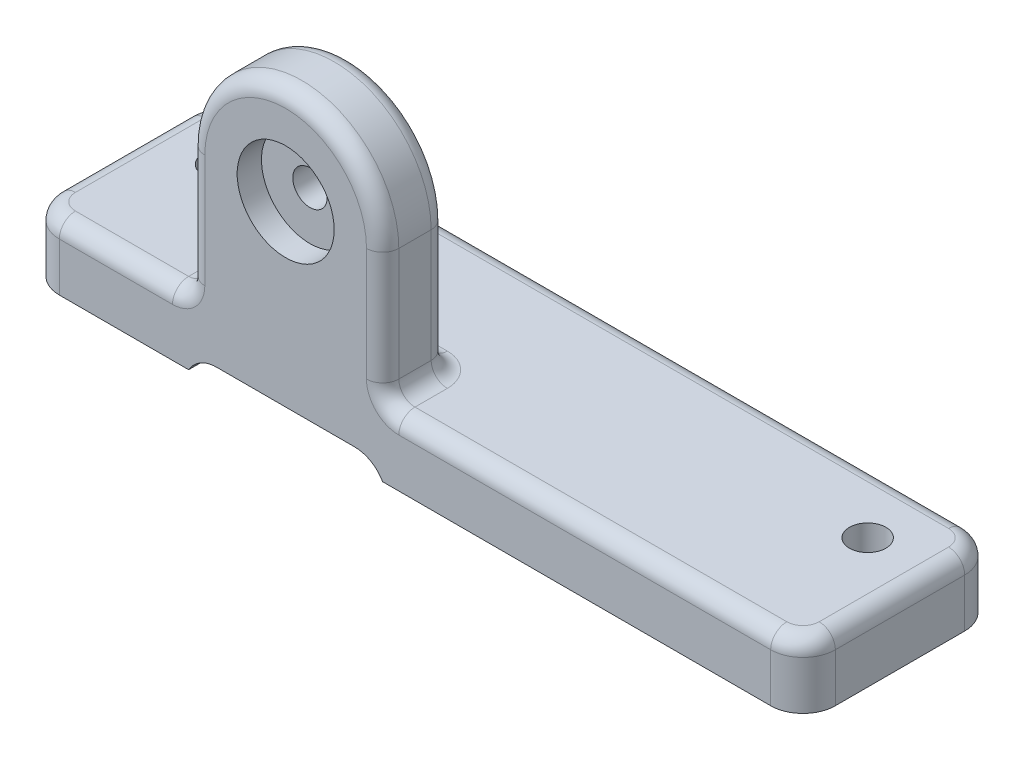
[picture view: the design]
ISO-10303-21;
HEADER;
FILE_DESCRIPTION(('STEP AP214'),'2;1');
FILE_NAME('part.step','',(''),(''),'','','');
FILE_SCHEMA(('AUTOMOTIVE_DESIGN { 1 0 10303 214 1 1 1 1 }'));
ENDSEC;
DATA;
#1=APPLICATION_CONTEXT('core data for automotive mechanical design processes');
#2=APPLICATION_PROTOCOL_DEFINITION('international standard','automotive_design',2000,#1);
#3=PRODUCT_CONTEXT('',#1,'mechanical');
#4=PRODUCT('Part','Part','',(#3));
#5=PRODUCT_RELATED_PRODUCT_CATEGORY('part','',(#4));
#6=PRODUCT_DEFINITION_FORMATION('','',#4);
#7=PRODUCT_DEFINITION_CONTEXT('part definition',#1,'design');
#8=PRODUCT_DEFINITION('design','',#6,#7);
#9=PRODUCT_DEFINITION_SHAPE('','',#8);
#10=(LENGTH_UNIT() NAMED_UNIT(*) SI_UNIT(.MILLI.,.METRE.));
#11=(NAMED_UNIT(*) PLANE_ANGLE_UNIT() SI_UNIT($,.RADIAN.));
#12=(NAMED_UNIT(*) SI_UNIT($,.STERADIAN.) SOLID_ANGLE_UNIT());
#13=UNCERTAINTY_MEASURE_WITH_UNIT(LENGTH_MEASURE(1.E-05),#10,'distance_accuracy_value','');
#14=(GEOMETRIC_REPRESENTATION_CONTEXT(3) GLOBAL_UNCERTAINTY_ASSIGNED_CONTEXT((#13)) GLOBAL_UNIT_ASSIGNED_CONTEXT((#10,
#11,#12)) REPRESENTATION_CONTEXT('',''));
#15=CARTESIAN_POINT('',(0.,0.,0.));
#16=DIRECTION('',(0.,0.,1.));
#17=DIRECTION('',(1.,0.,0.));
#18=AXIS2_PLACEMENT_3D('',#15,#16,#17);
#19=CARTESIAN_POINT('',(0.,0.,-38.1));
#20=DIRECTION('',(0.,-1.,0.));
#21=DIRECTION('',(0.,0.,-1.));
#22=AXIS2_PLACEMENT_3D('',#19,#20,#21);
#23=PLANE('',#22);
#24=CARTESIAN_POINT('',(12.7,0.,-25.4));
#25=DIRECTION('',(0.,1.,0.));
#26=DIRECTION('',(0.,0.,1.));
#27=AXIS2_PLACEMENT_3D('',#24,#25,#26);
#28=CIRCLE('',#27,3.571875);
#29=CARTESIAN_POINT('',(12.7,0.,-21.828125));
#30=VERTEX_POINT('',#29);
#31=EDGE_CURVE('E482',#30,#30,#28,.T.);
#32=ORIENTED_EDGE('',*,*,#31,.T.);
#33=EDGE_LOOP('',(#32));
#34=FACE_BOUND('',#33,.T.);
#35=DIRECTION('',(0.,0.,1.));
#36=VECTOR('',#35,1.);
#37=CARTESIAN_POINT('',(0.,0.,0.));
#38=LINE('',#37,#36);
#39=CARTESIAN_POINT('',(0.,0.,-31.75));
#40=VERTEX_POINT('',#39);
#41=CARTESIAN_POINT('',(0.,0.,-6.35));
#42=VERTEX_POINT('',#41);
#43=EDGE_CURVE('E273',#40,#42,#38,.T.);
#44=ORIENTED_EDGE('',*,*,#43,.F.);
#45=CARTESIAN_POINT('',(6.35,0.,-31.75));
#46=DIRECTION('',(0.,-1.,0.));
#47=DIRECTION('',(0.,0.,-1.));
#48=AXIS2_PLACEMENT_3D('',#45,#46,#47);
#49=CIRCLE('',#48,6.35);
#50=CARTESIAN_POINT('',(6.35,0.,-38.1));
#51=VERTEX_POINT('',#50);
#52=EDGE_CURVE('E247',#40,#51,#49,.T.);
#53=ORIENTED_EDGE('',*,*,#52,.T.);
#54=DIRECTION('',(-1.,0.,0.));
#55=VECTOR('',#54,1.);
#56=CARTESIAN_POINT('',(0.,0.,-38.1));
#57=LINE('',#56,#55);
#58=CARTESIAN_POINT('',(31.75,0.,-38.1));
#59=VERTEX_POINT('',#58);
#60=EDGE_CURVE('E235',#59,#51,#57,.T.);
#61=ORIENTED_EDGE('',*,*,#60,.F.);
#62=DIRECTION('',(0.,0.,1.));
#63=VECTOR('',#62,1.);
#64=CARTESIAN_POINT('',(31.75,0.,-38.1));
#65=LINE('',#64,#63);
#66=CARTESIAN_POINT('',(31.75,0.,0.));
#67=VERTEX_POINT('',#66);
#68=EDGE_CURVE('E246',#59,#67,#65,.T.);
#69=ORIENTED_EDGE('',*,*,#68,.T.);
#70=DIRECTION('',(1.,0.,0.));
#71=VECTOR('',#70,1.);
#72=CARTESIAN_POINT('',(0.,0.,0.));
#73=LINE('',#72,#71);
#74=CARTESIAN_POINT('',(6.35,0.,0.));
#75=VERTEX_POINT('',#74);
#76=EDGE_CURVE('E281',#75,#67,#73,.T.);
#77=ORIENTED_EDGE('',*,*,#76,.F.);
#78=CARTESIAN_POINT('',(6.35,0.,-6.35));
#79=DIRECTION('',(0.,-1.,0.));
#80=DIRECTION('',(0.,0.,-1.));
#81=AXIS2_PLACEMENT_3D('',#78,#79,#80);
#82=CIRCLE('',#81,6.35);
#83=EDGE_CURVE('E314',#75,#42,#82,.T.);
#84=ORIENTED_EDGE('',*,*,#83,.T.);
#85=EDGE_LOOP('',(#44,#53,#61,#69,#77,#84));
#86=FACE_BOUND('',#85,.T.);
#87=ADVANCED_FACE('F43',(#34,#86),#23,.T.);
#88=CARTESIAN_POINT('',(0.,12.7,0.));
#89=DIRECTION('',(1.,0.,0.));
#90=DIRECTION('',(0.,0.,-1.));
#91=AXIS2_PLACEMENT_3D('',#88,#89,#90);
#92=PLANE('',#91);
#93=DIRECTION('',(0.,-1.,0.));
#94=VECTOR('',#93,1.);
#95=CARTESIAN_POINT('',(0.,12.7,-6.35));
#96=LINE('',#95,#94);
#97=CARTESIAN_POINT('',(0.,9.525,-6.35));
#98=VERTEX_POINT('',#97);
#99=EDGE_CURVE('E309',#42,#98,#96,.F.);
#100=ORIENTED_EDGE('',*,*,#99,.T.);
#101=DIRECTION('',(0.,0.,1.));
#102=VECTOR('',#101,1.);
#103=CARTESIAN_POINT('',(0.,9.525,0.));
#104=LINE('',#103,#102);
#105=CARTESIAN_POINT('',(0.,9.525,-31.75));
#106=VERTEX_POINT('',#105);
#107=EDGE_CURVE('E358',#98,#106,#104,.F.);
#108=ORIENTED_EDGE('',*,*,#107,.T.);
#109=DIRECTION('',(0.,-1.,0.));
#110=VECTOR('',#109,1.);
#111=CARTESIAN_POINT('',(0.,12.7,-31.75));
#112=LINE('',#111,#110);
#113=EDGE_CURVE('E312',#106,#40,#112,.T.);
#114=ORIENTED_EDGE('',*,*,#113,.T.);
#115=ORIENTED_EDGE('',*,*,#43,.T.);
#116=EDGE_LOOP('',(#100,#108,#114,#115));
#117=FACE_BOUND('',#116,.T.);
#118=ADVANCED_FACE('F506',(#117),#92,.F.);
#119=CARTESIAN_POINT('',(0.,12.7,0.));
#120=DIRECTION('',(0.,0.,-1.));
#121=DIRECTION('',(-1.,0.,0.));
#122=AXIS2_PLACEMENT_3D('',#119,#120,#121);
#123=PLANE('',#122);
#124=CARTESIAN_POINT('',(50.8,38.1,0.));
#125=DIRECTION('',(0.,0.,1.));
#126=DIRECTION('',(1.,0.,0.));
#127=AXIS2_PLACEMENT_3D('',#124,#125,#126);
#128=CIRCLE('',#127,9.52499999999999);
#129=CARTESIAN_POINT('',(60.325,38.1,0.));
#130=VERTEX_POINT('',#129);
#131=EDGE_CURVE('E268',#130,#130,#128,.T.);
#132=ORIENTED_EDGE('',*,*,#131,.F.);
#133=EDGE_LOOP('',(#132));
#134=FACE_BOUND('',#133,.T.);
#135=CARTESIAN_POINT('',(28.575,15.875,0.));
#136=DIRECTION('',(0.,0.,-1.));
#137=DIRECTION('',(-1.,0.,0.));
#138=AXIS2_PLACEMENT_3D('',#135,#136,#137);
#139=CIRCLE('',#138,6.35);
#140=CARTESIAN_POINT('',(28.575,9.525,0.));
#141=VERTEX_POINT('',#140);
#142=CARTESIAN_POINT('',(34.925,15.875,0.));
#143=VERTEX_POINT('',#142);
#144=EDGE_CURVE('E374',#141,#143,#139,.F.);
#145=ORIENTED_EDGE('',*,*,#144,.F.);
#146=DIRECTION('',(1.,0.,0.));
#147=VECTOR('',#146,1.);
#148=CARTESIAN_POINT('',(0.,9.525,0.));
#149=LINE('',#148,#147);
#150=CARTESIAN_POINT('',(6.35,9.525,0.));
#151=VERTEX_POINT('',#150);
#152=EDGE_CURVE('E377',#141,#151,#149,.F.);
#153=ORIENTED_EDGE('',*,*,#152,.T.);
#154=DIRECTION('',(0.,-1.,0.));
#155=VECTOR('',#154,1.);
#156=CARTESIAN_POINT('',(6.35,12.7,0.));
#157=LINE('',#156,#155);
#158=EDGE_CURVE('E297',#151,#75,#157,.T.);
#159=ORIENTED_EDGE('',*,*,#158,.T.);
#160=ORIENTED_EDGE('',*,*,#76,.T.);
#161=CARTESIAN_POINT('',(37.2492613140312,-3.175,0.));
#162=DIRECTION('',(0.,0.,-1.));
#163=DIRECTION('',(-1.,0.,0.));
#164=AXIS2_PLACEMENT_3D('',#161,#162,#163);
#165=CIRCLE('',#164,6.35);
#166=CARTESIAN_POINT('',(37.2492613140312,3.175,0.));
#167=VERTEX_POINT('',#166);
#168=EDGE_CURVE('E239',#67,#167,#165,.T.);
#169=ORIENTED_EDGE('',*,*,#168,.T.);
#170=DIRECTION('',(-1.,0.,0.));
#171=VECTOR('',#170,1.);
#172=CARTESIAN_POINT('',(31.75,3.175,0.));
#173=LINE('',#172,#171);
#174=CARTESIAN_POINT('',(64.3507386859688,3.175,0.));
#175=VERTEX_POINT('',#174);
#176=EDGE_CURVE('E256',#175,#167,#173,.T.);
#177=ORIENTED_EDGE('',*,*,#176,.F.);
#178=CARTESIAN_POINT('',(64.3507386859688,-3.175,0.));
#179=DIRECTION('',(0.,0.,-1.));
#180=DIRECTION('',(-1.,0.,0.));
#181=AXIS2_PLACEMENT_3D('',#178,#179,#180);
#182=CIRCLE('',#181,6.35);
#183=CARTESIAN_POINT('',(69.85,0.,0.));
#184=VERTEX_POINT('',#183);
#185=EDGE_CURVE('E319',#175,#184,#182,.T.);
#186=ORIENTED_EDGE('',*,*,#185,.T.);
#187=CARTESIAN_POINT('',(146.05,0.,0.));
#188=VERTEX_POINT('',#187);
#189=EDGE_CURVE('E278',#184,#188,#73,.T.);
#190=ORIENTED_EDGE('',*,*,#189,.T.);
#191=DIRECTION('',(0.,-1.,0.));
#192=VECTOR('',#191,1.);
#193=CARTESIAN_POINT('',(146.05,12.7,0.));
#194=LINE('',#193,#192);
#195=CARTESIAN_POINT('',(146.05,9.525,0.));
#196=VERTEX_POINT('',#195);
#197=EDGE_CURVE('E305',#188,#196,#194,.F.);
#198=ORIENTED_EDGE('',*,*,#197,.T.);
#199=DIRECTION('',(1.,0.,0.));
#200=VECTOR('',#199,1.);
#201=CARTESIAN_POINT('',(0.,9.525,0.));
#202=LINE('',#201,#200);
#203=CARTESIAN_POINT('',(73.025,9.525,0.));
#204=VERTEX_POINT('',#203);
#205=EDGE_CURVE('E373',#196,#204,#202,.F.);
#206=ORIENTED_EDGE('',*,*,#205,.T.);
#207=CARTESIAN_POINT('',(73.025,15.875,0.));
#208=DIRECTION('',(0.,0.,-1.));
#209=DIRECTION('',(-1.,0.,0.));
#210=AXIS2_PLACEMENT_3D('',#207,#208,#209);
#211=CIRCLE('',#210,6.35);
#212=CARTESIAN_POINT('',(66.675,15.875,0.));
#213=VERTEX_POINT('',#212);
#214=EDGE_CURVE('E369',#213,#204,#211,.F.);
#215=ORIENTED_EDGE('',*,*,#214,.F.);
#216=DIRECTION('',(0.,1.,0.));
#217=VECTOR('',#216,1.);
#218=CARTESIAN_POINT('',(66.675,38.1,0.));
#219=LINE('',#218,#217);
#220=CARTESIAN_POINT('',(66.675,38.1,0.));
#221=VERTEX_POINT('',#220);
#222=EDGE_CURVE('E364',#213,#221,#219,.T.);
#223=ORIENTED_EDGE('',*,*,#222,.T.);
#224=CARTESIAN_POINT('',(50.8,38.1,0.));
#225=DIRECTION('',(0.,0.,-1.));
#226=DIRECTION('',(-1.,0.,0.));
#227=AXIS2_PLACEMENT_3D('',#224,#225,#226);
#228=CIRCLE('',#227,15.875);
#229=CARTESIAN_POINT('',(34.925,38.1,0.));
#230=VERTEX_POINT('',#229);
#231=EDGE_CURVE('E366',#221,#230,#228,.F.);
#232=ORIENTED_EDGE('',*,*,#231,.T.);
#233=DIRECTION('',(0.,-1.,0.));
#234=VECTOR('',#233,1.);
#235=CARTESIAN_POINT('',(34.925,12.7,0.));
#236=LINE('',#235,#234);
#237=EDGE_CURVE('E368',#230,#143,#236,.T.);
#238=ORIENTED_EDGE('',*,*,#237,.T.);
#239=EDGE_LOOP('',(#145,#153,#159,#160,#169,#177,#186,#190,#198,#206,#215,#223,#232,#238));
#240=FACE_BOUND('',#239,.T.);
#241=ADVANCED_FACE('F498',(#134,#240),#123,.F.);
#242=CARTESIAN_POINT('',(152.4,12.7,0.));
#243=DIRECTION('',(-1.,0.,0.));
#244=DIRECTION('',(0.,0.,1.));
#245=AXIS2_PLACEMENT_3D('',#242,#243,#244);
#246=PLANE('',#245);
#247=DIRECTION('',(0.,-1.,0.));
#248=VECTOR('',#247,1.);
#249=CARTESIAN_POINT('',(152.4,12.7,-31.75));
#250=LINE('',#249,#248);
#251=CARTESIAN_POINT('',(152.4,0.,-31.75));
#252=VERTEX_POINT('',#251);
#253=CARTESIAN_POINT('',(152.4,9.525,-31.75));
#254=VERTEX_POINT('',#253);
#255=EDGE_CURVE('E300',#252,#254,#250,.F.);
#256=ORIENTED_EDGE('',*,*,#255,.T.);
#257=DIRECTION('',(0.,0.,-1.));
#258=VECTOR('',#257,1.);
#259=CARTESIAN_POINT('',(152.4,9.525,0.));
#260=LINE('',#259,#258);
#261=CARTESIAN_POINT('',(152.4,9.525,-6.35));
#262=VERTEX_POINT('',#261);
#263=EDGE_CURVE('E379',#254,#262,#260,.F.);
#264=ORIENTED_EDGE('',*,*,#263,.T.);
#265=DIRECTION('',(0.,-1.,0.));
#266=VECTOR('',#265,1.);
#267=CARTESIAN_POINT('',(152.4,12.7,-6.35));
#268=LINE('',#267,#266);
#269=CARTESIAN_POINT('',(152.4,0.,-6.35));
#270=VERTEX_POINT('',#269);
#271=EDGE_CURVE('E294',#262,#270,#268,.T.);
#272=ORIENTED_EDGE('',*,*,#271,.T.);
#273=DIRECTION('',(0.,0.,-1.));
#274=VECTOR('',#273,1.);
#275=CARTESIAN_POINT('',(152.4,0.,0.));
#276=LINE('',#275,#274);
#277=EDGE_CURVE('E249',#270,#252,#276,.T.);
#278=ORIENTED_EDGE('',*,*,#277,.T.);
#279=EDGE_LOOP('',(#256,#264,#272,#278));
#280=FACE_BOUND('',#279,.T.);
#281=ADVANCED_FACE('F547',(#280),#246,.F.);
#282=CARTESIAN_POINT('',(0.,12.7,-38.1));
#283=DIRECTION('',(0.,0.,1.));
#284=DIRECTION('',(1.,0.,0.));
#285=AXIS2_PLACEMENT_3D('',#282,#283,#284);
#286=PLANE('',#285);
#287=DIRECTION('',(0.,-1.,0.));
#288=VECTOR('',#287,1.);
#289=CARTESIAN_POINT('',(6.35,12.7,-38.1));
#290=LINE('',#289,#288);
#291=CARTESIAN_POINT('',(6.35,9.525,-38.1));
#292=VERTEX_POINT('',#291);
#293=EDGE_CURVE('E284',#51,#292,#290,.F.);
#294=ORIENTED_EDGE('',*,*,#293,.T.);
#295=DIRECTION('',(-1.,0.,0.));
#296=VECTOR('',#295,1.);
#297=CARTESIAN_POINT('',(0.,9.525,-38.1));
#298=LINE('',#297,#296);
#299=CARTESIAN_POINT('',(146.05,9.525,-38.1));
#300=VERTEX_POINT('',#299);
#301=EDGE_CURVE('E356',#292,#300,#298,.F.);
#302=ORIENTED_EDGE('',*,*,#301,.T.);
#303=DIRECTION('',(0.,-1.,0.));
#304=VECTOR('',#303,1.);
#305=CARTESIAN_POINT('',(146.05,12.7,-38.1));
#306=LINE('',#305,#304);
#307=CARTESIAN_POINT('',(146.05,0.,-38.1));
#308=VERTEX_POINT('',#307);
#309=EDGE_CURVE('E288',#300,#308,#306,.T.);
#310=ORIENTED_EDGE('',*,*,#309,.T.);
#311=CARTESIAN_POINT('',(69.85,0.,-38.1));
#312=VERTEX_POINT('',#311);
#313=EDGE_CURVE('E248',#308,#312,#57,.T.);
#314=ORIENTED_EDGE('',*,*,#313,.T.);
#315=CARTESIAN_POINT('',(64.3507386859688,-3.175,-38.1));
#316=DIRECTION('',(0.,0.,1.));
#317=DIRECTION('',(1.,0.,0.));
#318=AXIS2_PLACEMENT_3D('',#315,#316,#317);
#319=CIRCLE('',#318,6.35);
#320=CARTESIAN_POINT('',(64.3507386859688,3.175,-38.1));
#321=VERTEX_POINT('',#320);
#322=EDGE_CURVE('E318',#312,#321,#319,.T.);
#323=ORIENTED_EDGE('',*,*,#322,.T.);
#324=DIRECTION('',(-1.,0.,0.));
#325=VECTOR('',#324,1.);
#326=CARTESIAN_POINT('',(31.75,3.175,-38.1));
#327=LINE('',#326,#325);
#328=CARTESIAN_POINT('',(37.2492613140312,3.175,-38.1));
#329=VERTEX_POINT('',#328);
#330=EDGE_CURVE('E232',#321,#329,#327,.T.);
#331=ORIENTED_EDGE('',*,*,#330,.T.);
#332=CARTESIAN_POINT('',(37.2492613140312,-3.175,-38.1));
#333=DIRECTION('',(0.,0.,1.));
#334=DIRECTION('',(1.,0.,0.));
#335=AXIS2_PLACEMENT_3D('',#332,#333,#334);
#336=CIRCLE('',#335,6.35);
#337=EDGE_CURVE('E226',#329,#59,#336,.T.);
#338=ORIENTED_EDGE('',*,*,#337,.T.);
#339=ORIENTED_EDGE('',*,*,#60,.T.);
#340=EDGE_LOOP('',(#294,#302,#310,#314,#323,#331,#338,#339));
#341=FACE_BOUND('',#340,.T.);
#342=ADVANCED_FACE('F233',(#341),#286,.F.);
#343=CARTESIAN_POINT('',(0.,12.7,-38.1));
#344=DIRECTION('',(0.,-1.,0.));
#345=DIRECTION('',(0.,0.,-1.));
#346=AXIS2_PLACEMENT_3D('',#343,#344,#345);
#347=PLANE('',#346);
#348=DIRECTION('',(-1.,0.,0.));
#349=VECTOR('',#348,1.);
#350=CARTESIAN_POINT('',(0.,12.7,-34.925));
#351=LINE('',#350,#349);
#352=CARTESIAN_POINT('',(146.05,12.7,-34.925));
#353=VERTEX_POINT('',#352);
#354=CARTESIAN_POINT('',(6.35,12.7,-34.925));
#355=VERTEX_POINT('',#354);
#356=EDGE_CURVE('E346',#353,#355,#351,.T.);
#357=ORIENTED_EDGE('',*,*,#356,.T.);
#358=CARTESIAN_POINT('',(6.35,12.7,-31.75));
#359=DIRECTION('',(0.,-1.,0.));
#360=DIRECTION('',(0.,0.,-1.));
#361=AXIS2_PLACEMENT_3D('',#358,#359,#360);
#362=CIRCLE('',#361,3.175);
#363=CARTESIAN_POINT('',(3.175,12.7,-31.75));
#364=VERTEX_POINT('',#363);
#365=EDGE_CURVE('E349',#355,#364,#362,.F.);
#366=ORIENTED_EDGE('',*,*,#365,.T.);
#367=DIRECTION('',(0.,0.,1.));
#368=VECTOR('',#367,1.);
#369=CARTESIAN_POINT('',(3.175,12.7,-38.1));
#370=LINE('',#369,#368);
#371=CARTESIAN_POINT('',(3.175,12.7,-6.35));
#372=VERTEX_POINT('',#371);
#373=EDGE_CURVE('E347',#364,#372,#370,.T.);
#374=ORIENTED_EDGE('',*,*,#373,.T.);
#375=CARTESIAN_POINT('',(6.35,12.7,-6.35));
#376=DIRECTION('',(0.,-1.,0.));
#377=DIRECTION('',(0.,0.,-1.));
#378=AXIS2_PLACEMENT_3D('',#375,#376,#377);
#379=CIRCLE('',#378,3.175);
#380=CARTESIAN_POINT('',(6.35,12.7,-3.175));
#381=VERTEX_POINT('',#380);
#382=EDGE_CURVE('E341',#372,#381,#379,.F.);
#383=ORIENTED_EDGE('',*,*,#382,.T.);
#384=DIRECTION('',(1.,0.,0.));
#385=VECTOR('',#384,1.);
#386=CARTESIAN_POINT('',(0.,12.7,-3.175));
#387=LINE('',#386,#385);
#388=CARTESIAN_POINT('',(28.575,12.7,-3.175));
#389=VERTEX_POINT('',#388);
#390=EDGE_CURVE('E338',#381,#389,#387,.T.);
#391=ORIENTED_EDGE('',*,*,#390,.T.);
#392=DIRECTION('',(0.,0.,-1.));
#393=VECTOR('',#392,1.);
#394=CARTESIAN_POINT('',(28.575,12.7,-38.1));
#395=LINE('',#394,#393);
#396=CARTESIAN_POINT('',(28.575,12.7,-9.525));
#397=VERTEX_POINT('',#396);
#398=EDGE_CURVE('E337',#389,#397,#395,.T.);
#399=ORIENTED_EDGE('',*,*,#398,.T.);
#400=CARTESIAN_POINT('',(34.925,12.7,-9.525));
#401=DIRECTION('',(0.,-1.,0.));
#402=DIRECTION('',(0.,0.,-1.));
#403=AXIS2_PLACEMENT_3D('',#400,#401,#402);
#404=CIRCLE('',#403,6.35);
#405=CARTESIAN_POINT('',(34.925,12.7,-15.875));
#406=VERTEX_POINT('',#405);
#407=EDGE_CURVE('E333',#406,#397,#404,.F.);
#408=ORIENTED_EDGE('',*,*,#407,.F.);
#409=DIRECTION('',(1.,0.,0.));
#410=VECTOR('',#409,1.);
#411=CARTESIAN_POINT('',(0.,12.7,-15.875));
#412=LINE('',#411,#410);
#413=CARTESIAN_POINT('',(66.675,12.7,-15.875));
#414=VERTEX_POINT('',#413);
#415=EDGE_CURVE('E328',#406,#414,#412,.T.);
#416=ORIENTED_EDGE('',*,*,#415,.T.);
#417=CARTESIAN_POINT('',(66.675,12.7,-9.525));
#418=DIRECTION('',(0.,-1.,0.));
#419=DIRECTION('',(0.,0.,-1.));
#420=AXIS2_PLACEMENT_3D('',#417,#418,#419);
#421=CIRCLE('',#420,6.35);
#422=CARTESIAN_POINT('',(73.025,12.7,-9.525));
#423=VERTEX_POINT('',#422);
#424=EDGE_CURVE('E326',#423,#414,#421,.F.);
#425=ORIENTED_EDGE('',*,*,#424,.F.);
#426=DIRECTION('',(0.,0.,1.));
#427=VECTOR('',#426,1.);
#428=CARTESIAN_POINT('',(73.025,12.7,-38.1));
#429=LINE('',#428,#427);
#430=CARTESIAN_POINT('',(73.025,12.7,-3.175));
#431=VERTEX_POINT('',#430);
#432=EDGE_CURVE('E237',#423,#431,#429,.T.);
#433=ORIENTED_EDGE('',*,*,#432,.T.);
#434=DIRECTION('',(1.,0.,0.));
#435=VECTOR('',#434,1.);
#436=CARTESIAN_POINT('',(0.,12.7,-3.175));
#437=LINE('',#436,#435);
#438=CARTESIAN_POINT('',(146.05,12.7,-3.175));
#439=VERTEX_POINT('',#438);
#440=EDGE_CURVE('E321',#431,#439,#437,.T.);
#441=ORIENTED_EDGE('',*,*,#440,.T.);
#442=CARTESIAN_POINT('',(146.05,12.7,-6.35));
#443=DIRECTION('',(0.,-1.,0.));
#444=DIRECTION('',(0.,0.,-1.));
#445=AXIS2_PLACEMENT_3D('',#442,#443,#444);
#446=CIRCLE('',#445,3.175);
#447=CARTESIAN_POINT('',(149.225,12.7,-6.35));
#448=VERTEX_POINT('',#447);
#449=EDGE_CURVE('E332',#439,#448,#446,.F.);
#450=ORIENTED_EDGE('',*,*,#449,.T.);
#451=DIRECTION('',(0.,0.,-1.));
#452=VECTOR('',#451,1.);
#453=CARTESIAN_POINT('',(149.225,12.7,-38.1));
#454=LINE('',#453,#452);
#455=CARTESIAN_POINT('',(149.225,12.7,-31.75));
#456=VERTEX_POINT('',#455);
#457=EDGE_CURVE('E336',#448,#456,#454,.T.);
#458=ORIENTED_EDGE('',*,*,#457,.T.);
#459=CARTESIAN_POINT('',(146.05,12.7,-31.75));
#460=DIRECTION('',(0.,-1.,0.));
#461=DIRECTION('',(0.,0.,-1.));
#462=AXIS2_PLACEMENT_3D('',#459,#460,#461);
#463=CIRCLE('',#462,3.175);
#464=EDGE_CURVE('E345',#456,#353,#463,.F.);
#465=ORIENTED_EDGE('',*,*,#464,.T.);
#466=EDGE_LOOP('',(#357,#366,#374,#383,#391,#399,#408,#416,#425,#433,#441,#450,#458,#465));
#467=FACE_BOUND('',#466,.T.);
#468=CARTESIAN_POINT('',(139.7,12.7,-25.4));
#469=DIRECTION('',(0.,1.,0.));
#470=DIRECTION('',(0.,0.,1.));
#471=AXIS2_PLACEMENT_3D('',#468,#469,#470);
#472=CIRCLE('',#471,3.57187499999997);
#473=CARTESIAN_POINT('',(139.7,12.7,-21.828125));
#474=VERTEX_POINT('',#473);
#475=EDGE_CURVE('E479',#474,#474,#472,.T.);
#476=ORIENTED_EDGE('',*,*,#475,.F.);
#477=EDGE_LOOP('',(#476));
#478=FACE_BOUND('',#477,.T.);
#479=CARTESIAN_POINT('',(12.7,12.7,-25.4));
#480=DIRECTION('',(0.,1.,0.));
#481=DIRECTION('',(0.,0.,1.));
#482=AXIS2_PLACEMENT_3D('',#479,#480,#481);
#483=CIRCLE('',#482,3.57187499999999);
#484=CARTESIAN_POINT('',(12.7,12.7,-21.828125));
#485=VERTEX_POINT('',#484);
#486=EDGE_CURVE('E489',#485,#485,#483,.T.);
#487=ORIENTED_EDGE('',*,*,#486,.F.);
#488=EDGE_LOOP('',(#487));
#489=FACE_BOUND('',#488,.T.);
#490=ADVANCED_FACE('F594',(#467,#478,#489),#347,.F.);
#491=CARTESIAN_POINT('',(139.7,0.,-25.4));
#492=DIRECTION('',(0.,1.,0.));
#493=DIRECTION('',(0.,0.,1.));
#494=AXIS2_PLACEMENT_3D('',#491,#492,#493);
#495=CIRCLE('',#494,3.571875);
#496=CARTESIAN_POINT('',(139.7,0.,-21.828125));
#497=VERTEX_POINT('',#496);
#498=EDGE_CURVE('E471',#497,#497,#495,.T.);
#499=ORIENTED_EDGE('',*,*,#498,.T.);
#500=EDGE_LOOP('',(#499));
#501=FACE_BOUND('',#500,.T.);
#502=ORIENTED_EDGE('',*,*,#313,.F.);
#503=CARTESIAN_POINT('',(146.05,0.,-31.75));
#504=DIRECTION('',(0.,-1.,0.));
#505=DIRECTION('',(0.,0.,-1.));
#506=AXIS2_PLACEMENT_3D('',#503,#504,#505);
#507=CIRCLE('',#506,6.35);
#508=EDGE_CURVE('E291',#308,#252,#507,.T.);
#509=ORIENTED_EDGE('',*,*,#508,.T.);
#510=ORIENTED_EDGE('',*,*,#277,.F.);
#511=CARTESIAN_POINT('',(146.05,0.,-6.35));
#512=DIRECTION('',(0.,-1.,0.));
#513=DIRECTION('',(0.,0.,-1.));
#514=AXIS2_PLACEMENT_3D('',#511,#512,#513);
#515=CIRCLE('',#514,6.35);
#516=EDGE_CURVE('E293',#270,#188,#515,.T.);
#517=ORIENTED_EDGE('',*,*,#516,.T.);
#518=ORIENTED_EDGE('',*,*,#189,.F.);
#519=DIRECTION('',(0.,0.,1.));
#520=VECTOR('',#519,1.);
#521=CARTESIAN_POINT('',(69.85,0.,-38.1));
#522=LINE('',#521,#520);
#523=EDGE_CURVE('E251',#312,#184,#522,.T.);
#524=ORIENTED_EDGE('',*,*,#523,.F.);
#525=EDGE_LOOP('',(#502,#509,#510,#517,#518,#524));
#526=FACE_BOUND('',#525,.T.);
#527=ADVANCED_FACE('F626',(#501,#526),#23,.T.);
#528=CARTESIAN_POINT('',(31.75,0.,-12.7));
#529=DIRECTION('',(-1.,0.,0.));
#530=DIRECTION('',(0.,0.,1.));
#531=AXIS2_PLACEMENT_3D('',#528,#529,#530);
#532=PLANE('',#531);
#533=DIRECTION('',(0.,0.,1.));
#534=VECTOR('',#533,1.);
#535=CARTESIAN_POINT('',(31.75,38.1,-12.7));
#536=LINE('',#535,#534);
#537=CARTESIAN_POINT('',(31.75,38.1,-9.525));
#538=VERTEX_POINT('',#537);
#539=CARTESIAN_POINT('',(31.75,38.1,-3.175));
#540=VERTEX_POINT('',#539);
#541=EDGE_CURVE('E275',#538,#540,#536,.T.);
#542=ORIENTED_EDGE('',*,*,#541,.F.);
#543=DIRECTION('',(0.,-1.,0.));
#544=VECTOR('',#543,1.);
#545=CARTESIAN_POINT('',(31.75,0.,-9.525));
#546=LINE('',#545,#544);
#547=CARTESIAN_POINT('',(31.75,15.875,-9.525));
#548=VERTEX_POINT('',#547);
#549=EDGE_CURVE('E390',#538,#548,#546,.T.);
#550=ORIENTED_EDGE('',*,*,#549,.T.);
#551=DIRECTION('',(0.,0.,-1.));
#552=VECTOR('',#551,1.);
#553=CARTESIAN_POINT('',(31.75,15.875,-12.7));
#554=LINE('',#553,#552);
#555=CARTESIAN_POINT('',(31.75,15.875,-3.175));
#556=VERTEX_POINT('',#555);
#557=EDGE_CURVE('E381',#548,#556,#554,.F.);
#558=ORIENTED_EDGE('',*,*,#557,.T.);
#559=DIRECTION('',(0.,-1.,0.));
#560=VECTOR('',#559,1.);
#561=CARTESIAN_POINT('',(31.75,38.1,-3.175));
#562=LINE('',#561,#560);
#563=EDGE_CURVE('E385',#556,#540,#562,.F.);
#564=ORIENTED_EDGE('',*,*,#563,.T.);
#565=EDGE_LOOP('',(#542,#550,#558,#564));
#566=FACE_BOUND('',#565,.T.);
#567=ADVANCED_FACE('F634',(#566),#532,.T.);
#568=CARTESIAN_POINT('',(69.85,0.,-12.7));
#569=DIRECTION('',(1.,0.,0.));
#570=DIRECTION('',(0.,0.,-1.));
#571=AXIS2_PLACEMENT_3D('',#568,#569,#570);
#572=PLANE('',#571);
#573=DIRECTION('',(0.,0.,1.));
#574=VECTOR('',#573,1.);
#575=CARTESIAN_POINT('',(69.85,15.875,-12.7));
#576=LINE('',#575,#574);
#577=CARTESIAN_POINT('',(69.85,15.875,-3.175));
#578=VERTEX_POINT('',#577);
#579=CARTESIAN_POINT('',(69.85,15.875,-9.525));
#580=VERTEX_POINT('',#579);
#581=EDGE_CURVE('E55',#578,#580,#576,.F.);
#582=ORIENTED_EDGE('',*,*,#581,.T.);
#583=DIRECTION('',(0.,1.,0.));
#584=VECTOR('',#583,1.);
#585=CARTESIAN_POINT('',(69.85,0.,-9.525));
#586=LINE('',#585,#584);
#587=CARTESIAN_POINT('',(69.85,38.1,-9.525));
#588=VERTEX_POINT('',#587);
#589=EDGE_CURVE('E11',#580,#588,#586,.T.);
#590=ORIENTED_EDGE('',*,*,#589,.T.);
#591=DIRECTION('',(0.,0.,1.));
#592=VECTOR('',#591,1.);
#593=CARTESIAN_POINT('',(69.85,38.1,-12.7));
#594=LINE('',#593,#592);
#595=CARTESIAN_POINT('',(69.85,38.1,-3.175));
#596=VERTEX_POINT('',#595);
#597=EDGE_CURVE('E277',#588,#596,#594,.T.);
#598=ORIENTED_EDGE('',*,*,#597,.T.);
#599=DIRECTION('',(0.,1.,0.));
#600=VECTOR('',#599,1.);
#601=CARTESIAN_POINT('',(69.85,12.7,-3.175));
#602=LINE('',#601,#600);
#603=EDGE_CURVE('E64',#596,#578,#602,.F.);
#604=ORIENTED_EDGE('',*,*,#603,.T.);
#605=EDGE_LOOP('',(#582,#590,#598,#604));
#606=FACE_BOUND('',#605,.T.);
#607=ADVANCED_FACE('F639',(#606),#572,.T.);
#608=CARTESIAN_POINT('',(50.8,38.1,-12.7));
#609=DIRECTION('',(0.,0.,-1.));
#610=DIRECTION('',(-1.,0.,0.));
#611=AXIS2_PLACEMENT_3D('',#608,#609,#610);
#612=PLANE('',#611);
#613=DIRECTION('',(0.,1.,0.));
#614=VECTOR('',#613,1.);
#615=CARTESIAN_POINT('',(66.675,38.1,-12.7));
#616=LINE('',#615,#614);
#617=CARTESIAN_POINT('',(66.675,38.1,-12.7));
#618=VERTEX_POINT('',#617);
#619=CARTESIAN_POINT('',(66.675,15.875,-12.7));
#620=VERTEX_POINT('',#619);
#621=EDGE_CURVE('E391',#618,#620,#616,.F.);
#622=ORIENTED_EDGE('',*,*,#621,.T.);
#623=DIRECTION('',(1.,0.,0.));
#624=VECTOR('',#623,1.);
#625=CARTESIAN_POINT('',(50.8,15.875,-12.7));
#626=LINE('',#625,#624);
#627=CARTESIAN_POINT('',(34.925,15.875,-12.7));
#628=VERTEX_POINT('',#627);
#629=EDGE_CURVE('E400',#620,#628,#626,.F.);
#630=ORIENTED_EDGE('',*,*,#629,.T.);
#631=DIRECTION('',(0.,-1.,0.));
#632=VECTOR('',#631,1.);
#633=CARTESIAN_POINT('',(34.925,38.1,-12.7));
#634=LINE('',#633,#632);
#635=CARTESIAN_POINT('',(34.925,38.1,-12.7));
#636=VERTEX_POINT('',#635);
#637=EDGE_CURVE('E394',#628,#636,#634,.F.);
#638=ORIENTED_EDGE('',*,*,#637,.T.);
#639=CARTESIAN_POINT('',(50.8,38.1,-12.7));
#640=DIRECTION('',(0.,0.,-1.));
#641=DIRECTION('',(-1.,0.,0.));
#642=AXIS2_PLACEMENT_3D('',#639,#640,#641);
#643=CIRCLE('',#642,15.875);
#644=EDGE_CURVE('E392',#636,#618,#643,.T.);
#645=ORIENTED_EDGE('',*,*,#644,.T.);
#646=EDGE_LOOP('',(#622,#630,#638,#645));
#647=FACE_BOUND('',#646,.T.);
#648=CARTESIAN_POINT('',(50.8,38.1,-12.7));
#649=DIRECTION('',(0.,0.,-1.));
#650=DIRECTION('',(-1.,0.,0.));
#651=AXIS2_PLACEMENT_3D('',#648,#649,#650);
#652=CIRCLE('',#651,3.37819999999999);
#653=CARTESIAN_POINT('',(47.4218,38.1,-12.7));
#654=VERTEX_POINT('',#653);
#655=EDGE_CURVE('E272',#654,#654,#652,.T.);
#656=ORIENTED_EDGE('',*,*,#655,.F.);
#657=EDGE_LOOP('',(#656));
#658=FACE_BOUND('',#657,.T.);
#659=ADVANCED_FACE('F702',(#647,#658),#612,.T.);
#660=CARTESIAN_POINT('',(50.8,38.1,-12.7));
#661=DIRECTION('',(0.,0.,1.));
#662=DIRECTION('',(1.,0.,0.));
#663=AXIS2_PLACEMENT_3D('',#660,#661,#662);
#664=CYLINDRICAL_SURFACE('',#663,19.05);
#665=ORIENTED_EDGE('',*,*,#597,.F.);
#666=CARTESIAN_POINT('',(50.8,38.1,-9.525));
#667=DIRECTION('',(0.,0.,-1.));
#668=DIRECTION('',(-1.,0.,0.));
#669=AXIS2_PLACEMENT_3D('',#666,#667,#668);
#670=CIRCLE('',#669,19.05);
#671=EDGE_CURVE('E405',#588,#538,#670,.F.);
#672=ORIENTED_EDGE('',*,*,#671,.T.);
#673=ORIENTED_EDGE('',*,*,#541,.T.);
#674=CARTESIAN_POINT('',(50.8,38.1,-3.175));
#675=DIRECTION('',(0.,0.,-1.));
#676=DIRECTION('',(-1.,0.,0.));
#677=AXIS2_PLACEMENT_3D('',#674,#675,#676);
#678=CIRCLE('',#677,19.05);
#679=EDGE_CURVE('E396',#540,#596,#678,.T.);
#680=ORIENTED_EDGE('',*,*,#679,.T.);
#681=EDGE_LOOP('',(#665,#672,#673,#680));
#682=FACE_BOUND('',#681,.T.);
#683=ADVANCED_FACE('F709',(#682),#664,.T.);
#684=CARTESIAN_POINT('',(50.8,38.1,0.));
#685=DIRECTION('',(0.,0.,1.));
#686=DIRECTION('',(1.,0.,0.));
#687=AXIS2_PLACEMENT_3D('',#684,#685,#686);
#688=CYLINDRICAL_SURFACE('',#687,9.52499999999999);
#689=CARTESIAN_POINT('',(50.8,38.1,-4.7752));
#690=DIRECTION('',(0.,0.,1.));
#691=DIRECTION('',(1.,0.,0.));
#692=AXIS2_PLACEMENT_3D('',#689,#690,#691);
#693=CIRCLE('',#692,9.52499999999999);
#694=CARTESIAN_POINT('',(60.325,38.1,-4.7752));
#695=VERTEX_POINT('',#694);
#696=EDGE_CURVE('E264',#695,#695,#693,.T.);
#697=ORIENTED_EDGE('',*,*,#696,.F.);
#698=EDGE_LOOP('',(#697));
#699=FACE_BOUND('',#698,.T.);
#700=ORIENTED_EDGE('',*,*,#131,.T.);
#701=EDGE_LOOP('',(#700));
#702=FACE_BOUND('',#701,.T.);
#703=ADVANCED_FACE('F712',(#699,#702),#688,.F.);
#704=CARTESIAN_POINT('',(54.1782,38.1,-4.7752));
#705=DIRECTION('',(0.,0.,-1.));
#706=DIRECTION('',(-1.,0.,0.));
#707=AXIS2_PLACEMENT_3D('',#704,#705,#706);
#708=PLANE('',#707);
#709=CARTESIAN_POINT('',(50.8,38.1,-4.7752));
#710=DIRECTION('',(0.,0.,1.));
#711=DIRECTION('',(1.,0.,0.));
#712=AXIS2_PLACEMENT_3D('',#709,#710,#711);
#713=CIRCLE('',#712,3.3782);
#714=CARTESIAN_POINT('',(54.1782,38.1,-4.7752));
#715=VERTEX_POINT('',#714);
#716=EDGE_CURVE('E260',#715,#715,#713,.T.);
#717=ORIENTED_EDGE('',*,*,#716,.F.);
#718=EDGE_LOOP('',(#717));
#719=FACE_BOUND('',#718,.T.);
#720=ORIENTED_EDGE('',*,*,#696,.T.);
#721=EDGE_LOOP('',(#720));
#722=FACE_BOUND('',#721,.T.);
#723=ADVANCED_FACE('F717',(#719,#722),#708,.F.);
#724=CARTESIAN_POINT('',(50.8,38.1,0.));
#725=DIRECTION('',(0.,0.,1.));
#726=DIRECTION('',(1.,0.,0.));
#727=AXIS2_PLACEMENT_3D('',#724,#725,#726);
#728=CYLINDRICAL_SURFACE('',#727,3.37819999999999);
#729=ORIENTED_EDGE('',*,*,#655,.T.);
#730=EDGE_LOOP('',(#729));
#731=FACE_BOUND('',#730,.T.);
#732=ORIENTED_EDGE('',*,*,#716,.T.);
#733=EDGE_LOOP('',(#732));
#734=FACE_BOUND('',#733,.T.);
#735=ADVANCED_FACE('F742',(#731,#734),#728,.F.);
#736=CARTESIAN_POINT('',(31.75,3.175,-38.1));
#737=DIRECTION('',(0.,1.,0.));
#738=DIRECTION('',(0.,0.,1.));
#739=AXIS2_PLACEMENT_3D('',#736,#737,#738);
#740=PLANE('',#739);
#741=ORIENTED_EDGE('',*,*,#330,.F.);
#742=DIRECTION('',(0.,0.,-1.));
#743=VECTOR('',#742,1.);
#744=CARTESIAN_POINT('',(64.3507386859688,3.175,-38.1));
#745=LINE('',#744,#743);
#746=EDGE_CURVE('E310',#321,#175,#745,.F.);
#747=ORIENTED_EDGE('',*,*,#746,.T.);
#748=ORIENTED_EDGE('',*,*,#176,.T.);
#749=DIRECTION('',(0.,0.,1.));
#750=VECTOR('',#749,1.);
#751=CARTESIAN_POINT('',(37.2492613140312,3.175,-38.1));
#752=LINE('',#751,#750);
#753=EDGE_CURVE('E304',#167,#329,#752,.F.);
#754=ORIENTED_EDGE('',*,*,#753,.T.);
#755=EDGE_LOOP('',(#741,#747,#748,#754));
#756=FACE_BOUND('',#755,.T.);
#757=ADVANCED_FACE('F492',(#756),#740,.F.);
#758=CARTESIAN_POINT('',(12.7,12.7,-25.4));
#759=DIRECTION('',(0.,1.,0.));
#760=DIRECTION('',(0.,0.,1.));
#761=AXIS2_PLACEMENT_3D('',#758,#759,#760);
#762=CYLINDRICAL_SURFACE('',#761,3.57187499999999);
#763=ORIENTED_EDGE('',*,*,#31,.F.);
#764=EDGE_LOOP('',(#763));
#765=FACE_BOUND('',#764,.T.);
#766=ORIENTED_EDGE('',*,*,#486,.T.);
#767=EDGE_LOOP('',(#766));
#768=FACE_BOUND('',#767,.T.);
#769=ADVANCED_FACE('F765',(#765,#768),#762,.F.);
#770=CARTESIAN_POINT('',(139.7,12.7,-25.4));
#771=DIRECTION('',(0.,1.,0.));
#772=DIRECTION('',(0.,0.,1.));
#773=AXIS2_PLACEMENT_3D('',#770,#771,#772);
#774=CYLINDRICAL_SURFACE('',#773,3.57187499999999);
#775=ORIENTED_EDGE('',*,*,#498,.F.);
#776=EDGE_LOOP('',(#775));
#777=FACE_BOUND('',#776,.T.);
#778=ORIENTED_EDGE('',*,*,#475,.T.);
#779=EDGE_LOOP('',(#778));
#780=FACE_BOUND('',#779,.T.);
#781=ADVANCED_FACE('F767',(#777,#780),#774,.F.);
#782=CARTESIAN_POINT('',(146.05,12.7,-31.75));
#783=DIRECTION('',(0.,-1.,0.));
#784=DIRECTION('',(0.,0.,-1.));
#785=AXIS2_PLACEMENT_3D('',#782,#783,#784);
#786=CYLINDRICAL_SURFACE('',#785,6.35);
#787=ORIENTED_EDGE('',*,*,#309,.F.);
#788=CARTESIAN_POINT('',(146.05,9.525,-31.75));
#789=DIRECTION('',(0.,-1.,0.));
#790=DIRECTION('',(0.,0.,-1.));
#791=AXIS2_PLACEMENT_3D('',#788,#789,#790);
#792=CIRCLE('',#791,6.35);
#793=EDGE_CURVE('E365',#300,#254,#792,.T.);
#794=ORIENTED_EDGE('',*,*,#793,.T.);
#795=ORIENTED_EDGE('',*,*,#255,.F.);
#796=ORIENTED_EDGE('',*,*,#508,.F.);
#797=EDGE_LOOP('',(#787,#794,#795,#796));
#798=FACE_BOUND('',#797,.T.);
#799=ADVANCED_FACE('F537',(#798),#786,.T.);
#800=CARTESIAN_POINT('',(146.05,12.7,-6.35));
#801=DIRECTION('',(0.,-1.,0.));
#802=DIRECTION('',(0.,0.,-1.));
#803=AXIS2_PLACEMENT_3D('',#800,#801,#802);
#804=CYLINDRICAL_SURFACE('',#803,6.35);
#805=ORIENTED_EDGE('',*,*,#271,.F.);
#806=CARTESIAN_POINT('',(146.05,9.525,-6.35));
#807=DIRECTION('',(0.,-1.,0.));
#808=DIRECTION('',(0.,0.,-1.));
#809=AXIS2_PLACEMENT_3D('',#806,#807,#808);
#810=CIRCLE('',#809,6.35);
#811=EDGE_CURVE('E386',#262,#196,#810,.T.);
#812=ORIENTED_EDGE('',*,*,#811,.T.);
#813=ORIENTED_EDGE('',*,*,#197,.F.);
#814=ORIENTED_EDGE('',*,*,#516,.F.);
#815=EDGE_LOOP('',(#805,#812,#813,#814));
#816=FACE_BOUND('',#815,.T.);
#817=ADVANCED_FACE('F555',(#816),#804,.T.);
#818=CARTESIAN_POINT('',(64.3507386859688,-3.175,-38.1));
#819=DIRECTION('',(0.,0.,-1.));
#820=DIRECTION('',(-1.,0.,0.));
#821=AXIS2_PLACEMENT_3D('',#818,#819,#820);
#822=CYLINDRICAL_SURFACE('',#821,6.35);
#823=ORIENTED_EDGE('',*,*,#322,.F.);
#824=ORIENTED_EDGE('',*,*,#523,.T.);
#825=ORIENTED_EDGE('',*,*,#185,.F.);
#826=ORIENTED_EDGE('',*,*,#746,.F.);
#827=EDGE_LOOP('',(#823,#824,#825,#826));
#828=FACE_BOUND('',#827,.T.);
#829=ADVANCED_FACE('F649',(#828),#822,.F.);
#830=CARTESIAN_POINT('',(37.2492613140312,-3.175,-38.1));
#831=DIRECTION('',(0.,0.,1.));
#832=DIRECTION('',(1.,0.,0.));
#833=AXIS2_PLACEMENT_3D('',#830,#831,#832);
#834=CYLINDRICAL_SURFACE('',#833,6.35);
#835=ORIENTED_EDGE('',*,*,#337,.F.);
#836=ORIENTED_EDGE('',*,*,#753,.F.);
#837=ORIENTED_EDGE('',*,*,#168,.F.);
#838=ORIENTED_EDGE('',*,*,#68,.F.);
#839=EDGE_LOOP('',(#835,#836,#837,#838));
#840=FACE_BOUND('',#839,.T.);
#841=ADVANCED_FACE('F255',(#840),#834,.F.);
#842=CARTESIAN_POINT('',(6.35,12.7,-31.75));
#843=DIRECTION('',(0.,-1.,0.));
#844=DIRECTION('',(0.,0.,-1.));
#845=AXIS2_PLACEMENT_3D('',#842,#843,#844);
#846=CYLINDRICAL_SURFACE('',#845,6.35);
#847=ORIENTED_EDGE('',*,*,#113,.F.);
#848=CARTESIAN_POINT('',(6.35,9.525,-31.75));
#849=DIRECTION('',(0.,-1.,0.));
#850=DIRECTION('',(0.,0.,-1.));
#851=AXIS2_PLACEMENT_3D('',#848,#849,#850);
#852=CIRCLE('',#851,6.35);
#853=EDGE_CURVE('E355',#106,#292,#852,.T.);
#854=ORIENTED_EDGE('',*,*,#853,.T.);
#855=ORIENTED_EDGE('',*,*,#293,.F.);
#856=ORIENTED_EDGE('',*,*,#52,.F.);
#857=EDGE_LOOP('',(#847,#854,#855,#856));
#858=FACE_BOUND('',#857,.T.);
#859=ADVANCED_FACE('F525',(#858),#846,.T.);
#860=CARTESIAN_POINT('',(6.35,12.7,-6.35));
#861=DIRECTION('',(0.,-1.,0.));
#862=DIRECTION('',(0.,0.,-1.));
#863=AXIS2_PLACEMENT_3D('',#860,#861,#862);
#864=CYLINDRICAL_SURFACE('',#863,6.35);
#865=ORIENTED_EDGE('',*,*,#158,.F.);
#866=CARTESIAN_POINT('',(6.35,9.525,-6.35));
#867=DIRECTION('',(0.,-1.,0.));
#868=DIRECTION('',(0.,0.,-1.));
#869=AXIS2_PLACEMENT_3D('',#866,#867,#868);
#870=CIRCLE('',#869,6.35);
#871=EDGE_CURVE('E359',#151,#98,#870,.T.);
#872=ORIENTED_EDGE('',*,*,#871,.T.);
#873=ORIENTED_EDGE('',*,*,#99,.F.);
#874=ORIENTED_EDGE('',*,*,#83,.F.);
#875=EDGE_LOOP('',(#865,#872,#873,#874));
#876=FACE_BOUND('',#875,.T.);
#877=ADVANCED_FACE('F508',(#876),#864,.T.);
#878=CARTESIAN_POINT('',(66.675,0.,-9.525));
#879=DIRECTION('',(0.,1.,0.));
#880=DIRECTION('',(0.,0.,1.));
#881=AXIS2_PLACEMENT_3D('',#878,#879,#880);
#882=CYLINDRICAL_SURFACE('',#881,3.175);
#883=CARTESIAN_POINT('',(66.675,15.875,-9.525));
#884=DIRECTION('',(0.,-1.,0.));
#885=DIRECTION('',(0.,0.,-1.));
#886=AXIS2_PLACEMENT_3D('',#883,#884,#885);
#887=CIRCLE('',#886,3.175);
#888=EDGE_CURVE('E50',#620,#580,#887,.T.);
#889=ORIENTED_EDGE('',*,*,#888,.F.);
#890=ORIENTED_EDGE('',*,*,#621,.F.);
#891=CARTESIAN_POINT('',(66.675,38.1,-9.525));
#892=DIRECTION('',(0.,1.,0.));
#893=DIRECTION('',(0.,0.,1.));
#894=AXIS2_PLACEMENT_3D('',#891,#892,#893);
#895=CIRCLE('',#894,3.175);
#896=EDGE_CURVE('E470',#588,#618,#895,.T.);
#897=ORIENTED_EDGE('',*,*,#896,.F.);
#898=ORIENTED_EDGE('',*,*,#589,.F.);
#899=EDGE_LOOP('',(#889,#890,#897,#898));
#900=FACE_BOUND('',#899,.T.);
#901=ADVANCED_FACE('F44',(#900),#882,.T.);
#902=CARTESIAN_POINT('',(66.675,15.875,-9.525));
#903=DIRECTION('',(0.,-1.,0.));
#904=DIRECTION('',(0.,0.,-1.));
#905=AXIS2_PLACEMENT_3D('',#902,#903,#904);
#906=TOROIDAL_SURFACE('',#905,6.35,3.175);
#907=CARTESIAN_POINT('',(66.675,15.875,-15.875));
#908=DIRECTION('',(-1.,0.,0.));
#909=DIRECTION('',(0.,0.,1.));
#910=AXIS2_PLACEMENT_3D('',#907,#908,#909);
#911=CIRCLE('',#910,3.175);
#912=EDGE_CURVE('E465',#620,#414,#911,.F.);
#913=ORIENTED_EDGE('',*,*,#912,.F.);
#914=ORIENTED_EDGE('',*,*,#888,.T.);
#915=CARTESIAN_POINT('',(73.025,15.875,-9.525));
#916=DIRECTION('',(0.,0.,1.));
#917=DIRECTION('',(1.,0.,0.));
#918=AXIS2_PLACEMENT_3D('',#915,#916,#917);
#919=CIRCLE('',#918,3.175);
#920=EDGE_CURVE('E461',#423,#580,#919,.F.);
#921=ORIENTED_EDGE('',*,*,#920,.F.);
#922=ORIENTED_EDGE('',*,*,#424,.T.);
#923=EDGE_LOOP('',(#913,#914,#921,#922));
#924=FACE_BOUND('',#923,.T.);
#925=ADVANCED_FACE('F608',(#924),#906,.F.);
#926=CARTESIAN_POINT('',(50.8,38.1,-9.525));
#927=DIRECTION('',(0.,0.,-1.));
#928=DIRECTION('',(-1.,0.,0.));
#929=AXIS2_PLACEMENT_3D('',#926,#927,#928);
#930=TOROIDAL_SURFACE('',#929,15.875,3.175);
#931=ORIENTED_EDGE('',*,*,#896,.T.);
#932=ORIENTED_EDGE('',*,*,#644,.F.);
#933=CARTESIAN_POINT('',(34.925,38.1,-9.525));
#934=DIRECTION('',(0.,-1.,0.));
#935=DIRECTION('',(0.,0.,-1.));
#936=AXIS2_PLACEMENT_3D('',#933,#934,#935);
#937=CIRCLE('',#936,3.175);
#938=EDGE_CURVE('E458',#538,#636,#937,.T.);
#939=ORIENTED_EDGE('',*,*,#938,.F.);
#940=ORIENTED_EDGE('',*,*,#671,.F.);
#941=EDGE_LOOP('',(#931,#932,#939,#940));
#942=FACE_BOUND('',#941,.T.);
#943=ADVANCED_FACE('F613',(#942),#930,.T.);
#944=CARTESIAN_POINT('',(73.025,15.875,-38.1));
#945=DIRECTION('',(0.,0.,1.));
#946=DIRECTION('',(1.,0.,0.));
#947=AXIS2_PLACEMENT_3D('',#944,#945,#946);
#948=CYLINDRICAL_SURFACE('',#947,3.175);
#949=ORIENTED_EDGE('',*,*,#920,.T.);
#950=ORIENTED_EDGE('',*,*,#581,.F.);
#951=CARTESIAN_POINT('',(73.025,15.875,-3.175));
#952=DIRECTION('',(0.,0.,-1.));
#953=DIRECTION('',(-1.,0.,0.));
#954=AXIS2_PLACEMENT_3D('',#951,#952,#953);
#955=CIRCLE('',#954,3.175);
#956=EDGE_CURVE('E454',#431,#578,#955,.T.);
#957=ORIENTED_EDGE('',*,*,#956,.F.);
#958=ORIENTED_EDGE('',*,*,#432,.F.);
#959=EDGE_LOOP('',(#949,#950,#957,#958));
#960=FACE_BOUND('',#959,.T.);
#961=ADVANCED_FACE('F611',(#960),#948,.F.);
#962=CARTESIAN_POINT('',(0.,15.875,-15.875));
#963=DIRECTION('',(1.,0.,0.));
#964=DIRECTION('',(0.,0.,-1.));
#965=AXIS2_PLACEMENT_3D('',#962,#963,#964);
#966=CYLINDRICAL_SURFACE('',#965,3.175);
#967=ORIENTED_EDGE('',*,*,#912,.T.);
#968=ORIENTED_EDGE('',*,*,#415,.F.);
#969=CARTESIAN_POINT('',(34.925,15.875,-15.875));
#970=DIRECTION('',(1.,0.,0.));
#971=DIRECTION('',(0.,0.,-1.));
#972=AXIS2_PLACEMENT_3D('',#969,#970,#971);
#973=CIRCLE('',#972,3.175);
#974=EDGE_CURVE('E448',#628,#406,#973,.T.);
#975=ORIENTED_EDGE('',*,*,#974,.F.);
#976=ORIENTED_EDGE('',*,*,#629,.F.);
#977=EDGE_LOOP('',(#967,#968,#975,#976));
#978=FACE_BOUND('',#977,.T.);
#979=ADVANCED_FACE('F606',(#978),#966,.F.);
#980=CARTESIAN_POINT('',(34.925,0.,-9.525));
#981=DIRECTION('',(0.,-1.,0.));
#982=DIRECTION('',(0.,0.,-1.));
#983=AXIS2_PLACEMENT_3D('',#980,#981,#982);
#984=CYLINDRICAL_SURFACE('',#983,3.175);
#985=ORIENTED_EDGE('',*,*,#938,.T.);
#986=ORIENTED_EDGE('',*,*,#637,.F.);
#987=CARTESIAN_POINT('',(34.925,15.875,-9.525));
#988=DIRECTION('',(0.,-1.,0.));
#989=DIRECTION('',(0.,0.,-1.));
#990=AXIS2_PLACEMENT_3D('',#987,#988,#989);
#991=CIRCLE('',#990,3.175);
#992=EDGE_CURVE('E449',#548,#628,#991,.T.);
#993=ORIENTED_EDGE('',*,*,#992,.F.);
#994=ORIENTED_EDGE('',*,*,#549,.F.);
#995=EDGE_LOOP('',(#985,#986,#993,#994));
#996=FACE_BOUND('',#995,.T.);
#997=ADVANCED_FACE('F619',(#996),#984,.T.);
#998=CARTESIAN_POINT('',(66.675,12.7,-3.175));
#999=DIRECTION('',(0.,-1.,0.));
#1000=DIRECTION('',(0.,0.,-1.));
#1001=AXIS2_PLACEMENT_3D('',#998,#999,#1000);
#1002=CYLINDRICAL_SURFACE('',#1001,3.175);
#1003=CARTESIAN_POINT('',(66.675,38.1,-3.175));
#1004=DIRECTION('',(0.,1.,0.));
#1005=DIRECTION('',(0.,0.,1.));
#1006=AXIS2_PLACEMENT_3D('',#1003,#1004,#1005);
#1007=CIRCLE('',#1006,3.175);
#1008=EDGE_CURVE('E444',#221,#596,#1007,.T.);
#1009=ORIENTED_EDGE('',*,*,#1008,.F.);
#1010=ORIENTED_EDGE('',*,*,#222,.F.);
#1011=CARTESIAN_POINT('',(66.675,15.875,-3.175));
#1012=DIRECTION('',(0.,-1.,0.));
#1013=DIRECTION('',(0.,0.,-1.));
#1014=AXIS2_PLACEMENT_3D('',#1011,#1012,#1013);
#1015=CIRCLE('',#1014,3.175);
#1016=EDGE_CURVE('E456',#578,#213,#1015,.T.);
#1017=ORIENTED_EDGE('',*,*,#1016,.F.);
#1018=ORIENTED_EDGE('',*,*,#603,.F.);
#1019=EDGE_LOOP('',(#1009,#1010,#1017,#1018));
#1020=FACE_BOUND('',#1019,.T.);
#1021=ADVANCED_FACE('F572',(#1020),#1002,.T.);
#1022=CARTESIAN_POINT('',(73.025,15.875,-3.175));
#1023=DIRECTION('',(0.,0.,-1.));
#1024=DIRECTION('',(-1.,0.,0.));
#1025=AXIS2_PLACEMENT_3D('',#1022,#1023,#1024);
#1026=TOROIDAL_SURFACE('',#1025,6.35,3.175);
#1027=ORIENTED_EDGE('',*,*,#1016,.T.);
#1028=ORIENTED_EDGE('',*,*,#214,.T.);
#1029=CARTESIAN_POINT('',(73.025,9.525,-3.175));
#1030=DIRECTION('',(-1.,0.,0.));
#1031=DIRECTION('',(0.,0.,1.));
#1032=AXIS2_PLACEMENT_3D('',#1029,#1030,#1031);
#1033=CIRCLE('',#1032,3.175);
#1034=EDGE_CURVE('E445',#431,#204,#1033,.F.);
#1035=ORIENTED_EDGE('',*,*,#1034,.F.);
#1036=ORIENTED_EDGE('',*,*,#956,.T.);
#1037=EDGE_LOOP('',(#1027,#1028,#1035,#1036));
#1038=FACE_BOUND('',#1037,.T.);
#1039=ADVANCED_FACE('F568',(#1038),#1026,.T.);
#1040=CARTESIAN_POINT('',(34.925,15.875,-9.525));
#1041=DIRECTION('',(0.,-1.,0.));
#1042=DIRECTION('',(0.,0.,-1.));
#1043=AXIS2_PLACEMENT_3D('',#1040,#1041,#1042);
#1044=TOROIDAL_SURFACE('',#1043,6.35,3.175);
#1045=ORIENTED_EDGE('',*,*,#974,.T.);
#1046=ORIENTED_EDGE('',*,*,#407,.T.);
#1047=CARTESIAN_POINT('',(28.575,15.875,-9.525));
#1048=DIRECTION('',(0.,0.,1.));
#1049=DIRECTION('',(1.,0.,0.));
#1050=AXIS2_PLACEMENT_3D('',#1047,#1048,#1049);
#1051=CIRCLE('',#1050,3.175);
#1052=EDGE_CURVE('E437',#548,#397,#1051,.F.);
#1053=ORIENTED_EDGE('',*,*,#1052,.F.);
#1054=ORIENTED_EDGE('',*,*,#992,.T.);
#1055=EDGE_LOOP('',(#1045,#1046,#1053,#1054));
#1056=FACE_BOUND('',#1055,.T.);
#1057=ADVANCED_FACE('F602',(#1056),#1044,.F.);
#1058=CARTESIAN_POINT('',(50.8,38.1,-3.175));
#1059=DIRECTION('',(0.,0.,-1.));
#1060=DIRECTION('',(-1.,0.,0.));
#1061=AXIS2_PLACEMENT_3D('',#1058,#1059,#1060);
#1062=TOROIDAL_SURFACE('',#1061,15.875,3.175);
#1063=ORIENTED_EDGE('',*,*,#1008,.T.);
#1064=ORIENTED_EDGE('',*,*,#679,.F.);
#1065=CARTESIAN_POINT('',(34.925,38.1,-3.175));
#1066=DIRECTION('',(0.,-1.,0.));
#1067=DIRECTION('',(0.,0.,-1.));
#1068=AXIS2_PLACEMENT_3D('',#1065,#1066,#1067);
#1069=CIRCLE('',#1068,3.175);
#1070=EDGE_CURVE('E436',#230,#540,#1069,.T.);
#1071=ORIENTED_EDGE('',*,*,#1070,.F.);
#1072=ORIENTED_EDGE('',*,*,#231,.F.);
#1073=EDGE_LOOP('',(#1063,#1064,#1071,#1072));
#1074=FACE_BOUND('',#1073,.T.);
#1075=ADVANCED_FACE('F578',(#1074),#1062,.T.);
#1076=CARTESIAN_POINT('',(0.,9.525,-3.175));
#1077=DIRECTION('',(1.,0.,0.));
#1078=DIRECTION('',(0.,0.,-1.));
#1079=AXIS2_PLACEMENT_3D('',#1076,#1077,#1078);
#1080=CYLINDRICAL_SURFACE('',#1079,3.175);
#1081=ORIENTED_EDGE('',*,*,#1034,.T.);
#1082=ORIENTED_EDGE('',*,*,#205,.F.);
#1083=CARTESIAN_POINT('',(146.05,9.525,-3.175));
#1084=DIRECTION('',(1.,0.,0.));
#1085=DIRECTION('',(0.,0.,-1.));
#1086=AXIS2_PLACEMENT_3D('',#1083,#1084,#1085);
#1087=CIRCLE('',#1086,3.175);
#1088=EDGE_CURVE('E433',#439,#196,#1087,.T.);
#1089=ORIENTED_EDGE('',*,*,#1088,.F.);
#1090=ORIENTED_EDGE('',*,*,#440,.F.);
#1091=EDGE_LOOP('',(#1081,#1082,#1089,#1090));
#1092=FACE_BOUND('',#1091,.T.);
#1093=ADVANCED_FACE('F562',(#1092),#1080,.T.);
#1094=CARTESIAN_POINT('',(28.575,15.875,-38.1));
#1095=DIRECTION('',(0.,0.,-1.));
#1096=DIRECTION('',(-1.,0.,0.));
#1097=AXIS2_PLACEMENT_3D('',#1094,#1095,#1096);
#1098=CYLINDRICAL_SURFACE('',#1097,3.175);
#1099=ORIENTED_EDGE('',*,*,#1052,.T.);
#1100=ORIENTED_EDGE('',*,*,#398,.F.);
#1101=CARTESIAN_POINT('',(28.575,15.875,-3.175));
#1102=DIRECTION('',(0.,0.,-1.));
#1103=DIRECTION('',(-1.,0.,0.));
#1104=AXIS2_PLACEMENT_3D('',#1101,#1102,#1103);
#1105=CIRCLE('',#1104,3.175);
#1106=EDGE_CURVE('E427',#556,#389,#1105,.T.);
#1107=ORIENTED_EDGE('',*,*,#1106,.F.);
#1108=ORIENTED_EDGE('',*,*,#557,.F.);
#1109=EDGE_LOOP('',(#1099,#1100,#1107,#1108));
#1110=FACE_BOUND('',#1109,.T.);
#1111=ADVANCED_FACE('F600',(#1110),#1098,.F.);
#1112=CARTESIAN_POINT('',(34.925,12.7,-3.175));
#1113=DIRECTION('',(0.,1.,0.));
#1114=DIRECTION('',(0.,0.,1.));
#1115=AXIS2_PLACEMENT_3D('',#1112,#1113,#1114);
#1116=CYLINDRICAL_SURFACE('',#1115,3.175);
#1117=ORIENTED_EDGE('',*,*,#1070,.T.);
#1118=ORIENTED_EDGE('',*,*,#563,.F.);
#1119=CARTESIAN_POINT('',(34.925,15.875,-3.175));
#1120=DIRECTION('',(0.,-1.,0.));
#1121=DIRECTION('',(0.,0.,-1.));
#1122=AXIS2_PLACEMENT_3D('',#1119,#1120,#1121);
#1123=CIRCLE('',#1122,3.175);
#1124=EDGE_CURVE('E426',#143,#556,#1123,.T.);
#1125=ORIENTED_EDGE('',*,*,#1124,.F.);
#1126=ORIENTED_EDGE('',*,*,#237,.F.);
#1127=EDGE_LOOP('',(#1117,#1118,#1125,#1126));
#1128=FACE_BOUND('',#1127,.T.);
#1129=ADVANCED_FACE('F584',(#1128),#1116,.T.);
#1130=CARTESIAN_POINT('',(146.05,9.525,-6.35));
#1131=DIRECTION('',(0.,-1.,0.));
#1132=DIRECTION('',(0.,0.,-1.));
#1133=AXIS2_PLACEMENT_3D('',#1130,#1131,#1132);
#1134=DEGENERATE_TOROIDAL_SURFACE('',#1133,3.175,3.175,.T.);
#1135=ORIENTED_EDGE('',*,*,#1088,.T.);
#1136=ORIENTED_EDGE('',*,*,#811,.F.);
#1137=CARTESIAN_POINT('',(149.225,9.525,-6.35));
#1138=DIRECTION('',(0.,0.,-1.));
#1139=DIRECTION('',(-1.,0.,0.));
#1140=AXIS2_PLACEMENT_3D('',#1137,#1138,#1139);
#1141=CIRCLE('',#1140,3.175);
#1142=EDGE_CURVE('E424',#448,#262,#1141,.T.);
#1143=ORIENTED_EDGE('',*,*,#1142,.F.);
#1144=ORIENTED_EDGE('',*,*,#449,.F.);
#1145=EDGE_LOOP('',(#1135,#1136,#1143,#1144));
#1146=FACE_BOUND('',#1145,.T.);
#1147=ADVANCED_FACE('F556',(#1146),#1134,.T.);
#1148=CARTESIAN_POINT('',(28.575,15.875,-3.175));
#1149=DIRECTION('',(0.,0.,-1.));
#1150=DIRECTION('',(-1.,0.,0.));
#1151=AXIS2_PLACEMENT_3D('',#1148,#1149,#1150);
#1152=TOROIDAL_SURFACE('',#1151,6.35,3.175);
#1153=ORIENTED_EDGE('',*,*,#1124,.T.);
#1154=ORIENTED_EDGE('',*,*,#1106,.T.);
#1155=CARTESIAN_POINT('',(28.575,9.525,-3.175));
#1156=DIRECTION('',(1.,0.,0.));
#1157=DIRECTION('',(0.,0.,-1.));
#1158=AXIS2_PLACEMENT_3D('',#1155,#1156,#1157);
#1159=CIRCLE('',#1158,3.175);
#1160=EDGE_CURVE('E422',#141,#389,#1159,.F.);
#1161=ORIENTED_EDGE('',*,*,#1160,.F.);
#1162=ORIENTED_EDGE('',*,*,#144,.T.);
#1163=EDGE_LOOP('',(#1153,#1154,#1161,#1162));
#1164=FACE_BOUND('',#1163,.T.);
#1165=ADVANCED_FACE('F590',(#1164),#1152,.T.);
#1166=CARTESIAN_POINT('',(149.225,9.525,-38.1));
#1167=DIRECTION('',(0.,0.,-1.));
#1168=DIRECTION('',(-1.,0.,0.));
#1169=AXIS2_PLACEMENT_3D('',#1166,#1167,#1168);
#1170=CYLINDRICAL_SURFACE('',#1169,3.175);
#1171=ORIENTED_EDGE('',*,*,#1142,.T.);
#1172=ORIENTED_EDGE('',*,*,#263,.F.);
#1173=CARTESIAN_POINT('',(149.225,9.525,-31.75));
#1174=DIRECTION('',(0.,0.,-1.));
#1175=DIRECTION('',(-1.,0.,0.));
#1176=AXIS2_PLACEMENT_3D('',#1173,#1174,#1175);
#1177=CIRCLE('',#1176,3.175);
#1178=EDGE_CURVE('E418',#456,#254,#1177,.T.);
#1179=ORIENTED_EDGE('',*,*,#1178,.F.);
#1180=ORIENTED_EDGE('',*,*,#457,.F.);
#1181=EDGE_LOOP('',(#1171,#1172,#1179,#1180));
#1182=FACE_BOUND('',#1181,.T.);
#1183=ADVANCED_FACE('F549',(#1182),#1170,.T.);
#1184=CARTESIAN_POINT('',(0.,9.525,-3.175));
#1185=DIRECTION('',(1.,0.,0.));
#1186=DIRECTION('',(0.,0.,-1.));
#1187=AXIS2_PLACEMENT_3D('',#1184,#1185,#1186);
#1188=CYLINDRICAL_SURFACE('',#1187,3.175);
#1189=ORIENTED_EDGE('',*,*,#1160,.T.);
#1190=ORIENTED_EDGE('',*,*,#390,.F.);
#1191=CARTESIAN_POINT('',(6.35,9.525,-3.175));
#1192=DIRECTION('',(-1.,0.,0.));
#1193=DIRECTION('',(0.,0.,1.));
#1194=AXIS2_PLACEMENT_3D('',#1191,#1192,#1193);
#1195=CIRCLE('',#1194,3.175);
#1196=EDGE_CURVE('E419',#151,#381,#1195,.T.);
#1197=ORIENTED_EDGE('',*,*,#1196,.F.);
#1198=ORIENTED_EDGE('',*,*,#152,.F.);
#1199=EDGE_LOOP('',(#1189,#1190,#1197,#1198));
#1200=FACE_BOUND('',#1199,.T.);
#1201=ADVANCED_FACE('F589',(#1200),#1188,.T.);
#1202=CARTESIAN_POINT('',(146.05,9.525,-31.75));
#1203=DIRECTION('',(0.,-1.,0.));
#1204=DIRECTION('',(0.,0.,-1.));
#1205=AXIS2_PLACEMENT_3D('',#1202,#1203,#1204);
#1206=DEGENERATE_TOROIDAL_SURFACE('',#1205,3.175,3.175,.T.);
#1207=ORIENTED_EDGE('',*,*,#1178,.T.);
#1208=ORIENTED_EDGE('',*,*,#793,.F.);
#1209=CARTESIAN_POINT('',(146.05,9.525,-34.925));
#1210=DIRECTION('',(-1.,0.,0.));
#1211=DIRECTION('',(0.,0.,1.));
#1212=AXIS2_PLACEMENT_3D('',#1209,#1210,#1211);
#1213=CIRCLE('',#1212,3.175);
#1214=EDGE_CURVE('E412',#353,#300,#1213,.T.);
#1215=ORIENTED_EDGE('',*,*,#1214,.F.);
#1216=ORIENTED_EDGE('',*,*,#464,.F.);
#1217=EDGE_LOOP('',(#1207,#1208,#1215,#1216));
#1218=FACE_BOUND('',#1217,.T.);
#1219=ADVANCED_FACE('F538',(#1218),#1206,.T.);
#1220=CARTESIAN_POINT('',(6.35,9.525,-6.35));
#1221=DIRECTION('',(0.,-1.,0.));
#1222=DIRECTION('',(0.,0.,-1.));
#1223=AXIS2_PLACEMENT_3D('',#1220,#1221,#1222);
#1224=DEGENERATE_TOROIDAL_SURFACE('',#1223,3.175,3.175,.T.);
#1225=ORIENTED_EDGE('',*,*,#1196,.T.);
#1226=ORIENTED_EDGE('',*,*,#382,.F.);
#1227=CARTESIAN_POINT('',(3.175,9.525,-6.35));
#1228=DIRECTION('',(0.,0.,-1.));
#1229=DIRECTION('',(-1.,0.,0.));
#1230=AXIS2_PLACEMENT_3D('',#1227,#1228,#1229);
#1231=CIRCLE('',#1230,3.175);
#1232=EDGE_CURVE('E408',#98,#372,#1231,.T.);
#1233=ORIENTED_EDGE('',*,*,#1232,.F.);
#1234=ORIENTED_EDGE('',*,*,#871,.F.);
#1235=EDGE_LOOP('',(#1225,#1226,#1233,#1234));
#1236=FACE_BOUND('',#1235,.T.);
#1237=ADVANCED_FACE('F514',(#1236),#1224,.T.);
#1238=CARTESIAN_POINT('',(0.,9.525,-34.925));
#1239=DIRECTION('',(-1.,0.,0.));
#1240=DIRECTION('',(0.,0.,1.));
#1241=AXIS2_PLACEMENT_3D('',#1238,#1239,#1240);
#1242=CYLINDRICAL_SURFACE('',#1241,3.175);
#1243=ORIENTED_EDGE('',*,*,#1214,.T.);
#1244=ORIENTED_EDGE('',*,*,#301,.F.);
#1245=CARTESIAN_POINT('',(6.35,9.525,-34.925));
#1246=DIRECTION('',(-1.,0.,0.));
#1247=DIRECTION('',(0.,0.,1.));
#1248=AXIS2_PLACEMENT_3D('',#1245,#1246,#1247);
#1249=CIRCLE('',#1248,3.175);
#1250=EDGE_CURVE('E409',#355,#292,#1249,.T.);
#1251=ORIENTED_EDGE('',*,*,#1250,.F.);
#1252=ORIENTED_EDGE('',*,*,#356,.F.);
#1253=EDGE_LOOP('',(#1243,#1244,#1251,#1252));
#1254=FACE_BOUND('',#1253,.T.);
#1255=ADVANCED_FACE('F526',(#1254),#1242,.T.);
#1256=CARTESIAN_POINT('',(3.175,9.525,-38.1));
#1257=DIRECTION('',(0.,0.,1.));
#1258=DIRECTION('',(1.,0.,0.));
#1259=AXIS2_PLACEMENT_3D('',#1256,#1257,#1258);
#1260=CYLINDRICAL_SURFACE('',#1259,3.175);
#1261=ORIENTED_EDGE('',*,*,#1232,.T.);
#1262=ORIENTED_EDGE('',*,*,#373,.F.);
#1263=CARTESIAN_POINT('',(3.175,9.525,-31.75));
#1264=DIRECTION('',(0.,0.,-1.));
#1265=DIRECTION('',(-1.,0.,0.));
#1266=AXIS2_PLACEMENT_3D('',#1263,#1264,#1265);
#1267=CIRCLE('',#1266,3.175);
#1268=EDGE_CURVE('E407',#106,#364,#1267,.T.);
#1269=ORIENTED_EDGE('',*,*,#1268,.F.);
#1270=ORIENTED_EDGE('',*,*,#107,.F.);
#1271=EDGE_LOOP('',(#1261,#1262,#1269,#1270));
#1272=FACE_BOUND('',#1271,.T.);
#1273=ADVANCED_FACE('F516',(#1272),#1260,.T.);
#1274=CARTESIAN_POINT('',(6.35,9.525,-31.75));
#1275=DIRECTION('',(0.,-1.,0.));
#1276=DIRECTION('',(0.,0.,-1.));
#1277=AXIS2_PLACEMENT_3D('',#1274,#1275,#1276);
#1278=DEGENERATE_TOROIDAL_SURFACE('',#1277,3.175,3.175,.T.);
#1279=ORIENTED_EDGE('',*,*,#1250,.T.);
#1280=ORIENTED_EDGE('',*,*,#853,.F.);
#1281=ORIENTED_EDGE('',*,*,#1268,.T.);
#1282=ORIENTED_EDGE('',*,*,#365,.F.);
#1283=EDGE_LOOP('',(#1279,#1280,#1281,#1282));
#1284=FACE_BOUND('',#1283,.T.);
#1285=ADVANCED_FACE('F523',(#1284),#1278,.T.);
#1286=CLOSED_SHELL('',(#87,#118,#241,#281,#342,#490,#527,#567,#607,#659,#683,#703,#723,#735,
#757,#769,#781,#799,#817,#829,#841,#859,#877,#901,#925,#943,#961,#979,#997,#1021,#1039,#1057,
#1075,#1093,#1111,#1129,#1147,#1165,#1183,#1201,#1219,#1237,#1255,#1273,#1285));
#1287=MANIFOLD_SOLID_BREP('B2',#1286);
#1288=ADVANCED_BREP_SHAPE_REPRESENTATION('',(#18,#1287),#14);
#1289=SHAPE_DEFINITION_REPRESENTATION(#9,#1288);
ENDSEC;
END-ISO-10303-21;
